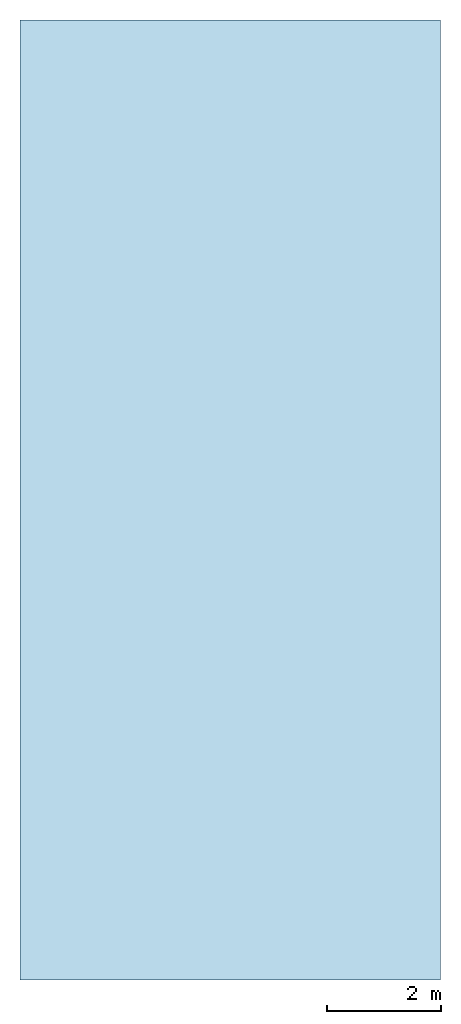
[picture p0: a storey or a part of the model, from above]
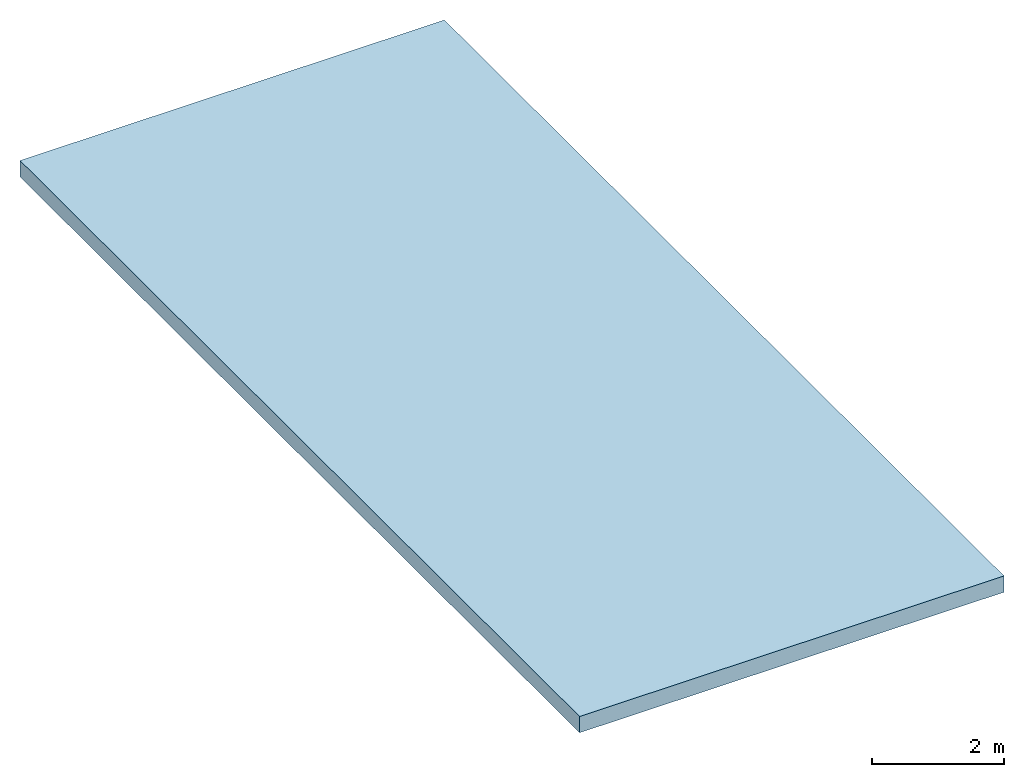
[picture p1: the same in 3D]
Properties of the parts of a building model (IFC2X3)

# File
Description: ViewDefinition [CoordinationView_V2.0]
File name: 0001
Time: 2020-11-30T17:44:46
Written by: The EXPRESS Data Manager Version 5.02.0100.07 : 28 Aug 2013
Made in: 21.0.0.383 - Exporter 21.0.0.383 - IU alternativa 21.0.0.383
Comment: STEP Physical File produced by: The EXPRESS Data Manager Version 5.02.0100.07 : 28 Aug 2013 * Module: EDMstepFileFactory/EDMstandAlone * Creation date: Mon Nov 30 17:44:46 2020 * Host: DESKTOP-IT14RNR * Database: C:\Users\CYPE\AppData\Local\Temp\9540b35c-920c-4d57-9700-88821f75c136\3319a0d3-95b9-443c-a24a-ebdda90667f6\ifc * Database version: 5507 * Database creation date: Mon Nov 30 17:44:29 2020 * Schema: IFC2X3 * Model: DataRepository.ifc * Model creation date: Mon Nov 30 17:44:29 2020 * Header model: DataRepository.ifc_HeaderModel * Header model creation date: Mon Nov 30 17:44:29 2020 * EDMuser: sdai-user * EDMgroup: sdai-group * License ID and type: 5605 : Permanent license. Expiry date: * EDMstepFileFactory options: 020000

# IfcProject, 0001
LongName: Nombre de proyecto; Phase: Estado de proyecto

# IfcSite, Default
RefLatitude: 40, 25, 13, 9643; RefLongitude: -3, -42, -20, -772056; RefElevation: 0 m

# IfcBuilding
Pset_BuildingCommon - NumberOfStoreys: 2

# IfcBuildingStorey: Nivel:Nivel 1 (2)
Name | LongName | Elevation (m)
Nivel 1 | Nivel 1 | 0
Nivel 2 | Nivel 2 | 3

# IfcCurtainWall: Muro cortina:Muro cortina - 300 x 200 cm, Muro cortina:Muro cortina - 300 x 200 cm:166910
In: Nivel 1
Type - Pset_CurtainWallCommon - IsExternal: no; Reference: Muro cortina - 300 x 200 cm
Type - Pset_QuantityTakeOff - Reference: Muro cortina - 300 x 200 cm
Pset_CurtainWallCommon - IsExternal: yes

# IfcDoor: Puerta de 1 hoja:80 x 210 cm, Puerta de 1 hoja:80 x 210 cm:166070
In: Nivel 1
Type - ParameterTakesPrecedence: no; Sizeable: no; Material: <Unnamed> (3), Madera - Castaño
Type - Pset_DoorCommon - IsExternal: no; Reference: 80 x 210 cm; ThermalTransmittance: 3.7021 kg/K/s3
Type - Pset_QuantityTakeOff - Reference: 80 x 210 cm
OverallHeight: 2.1 m; OverallWidth: 0.8 m; Material: Madera - Castaño

# IfcFurnishingElement: M_Chair-Breuer:M_Chair-Breuer (28)
In: Nivel 1
Type - Material: Steel, Chrome Plated, Textile - Bamboo Weave
Type - Pset_QuantityTakeOff - Reference: M_Chair-Breuer
Material: Textile - Bamboo Weave, Steel, Chrome Plated
Name (M_Chair-Breuer:M_Chair-Breuer:...)
165478
165479
165480
165481
165593
165594
165595
165596
165632
165633
165634
165635
165734
165735
165736
165737
165777
165778
165779
165780
165822
165823
165824
165825
165863
165864
165865
165866

# IfcFurnishingElement: M_Table-Dining Round w Chairs:0915mm Diameter (7)
In: Nivel 1
Type - Material: Laminate, Linen, Matte, Pine
Type - Pset_QuantityTakeOff - Reference: 0915mm Diameter
Material: Pine, Laminate, Linen, Matte
Name (M_Table-Dining Round w Chairs:0915mm Diameter:...)
165477
165592
165631
165733
165776
165821
165862

# IfcMember: Montante rectangular:Montante rectangular - 5 x 10 cm (31)
In: Nivel 1
Type - PredefinedType: MULLION; Material: <Unnamed>
Type - Pset_MemberCommon - IsExternal: no; Reference: Montante rectangular - 5 x 10 cm
Type - Pset_QuantityTakeOff - Reference: Montante rectangular - 5 x 10 cm
Pset_MemberCommon - IsExternal: yes
Name (Montante rectangular:Montante rectangular - 5 x 10 cm:...) | Span (m)
166943 | 0.958333
166944 | 0.958333
166955 | 0.958333
166956 | 0.958333
166957 | 0.958333
167001 | 0.983333
167002 | 0.958333
167003 | 0.958333
167004 | 0.983333
167005 | 0.983333
167006 | 0.958333
167007 | 0.983333
167008 | 0.958333
167009 | 0.983333
167010 | 0.958333
167011 | 1.7125
167012 | 1.7625
167013 | 1.7625
167014 | 1.7125
167015 | 1.7125
167016 | 1.7625
167017 | 1.7625
167018 | 1.7125
167101 | 1.7875
167102 | 1.7875
167103 | 1.8125
167104 | 1.8125
167105 | 1.7875
167106 | 1.8125
167107 | 1.8125
167108 | 1.7875

# IfcPlate: Panel de sistema:Acristalado (12)
In: Nivel 1
Type - PredefinedType: CURTAIN_PANEL; Material: Cristal
Type - Pset_PlateCommon - IsExternal: no; Reference: Acristalado; ThermalTransmittance: 6.7069 kg/K/s3
Type - Pset_QuantityTakeOff - Reference: Acristalado
Pset_PlateCommon - IsExternal: yes
Name (Panel de sistema:Acristalado:...)
166941
166946
166948
166950
166984
166985
166986
166987
166989
166990
166991
166992

# IfcSlab: Suelo:Por defecto - 30 cm (2)
Type - PredefinedType: FLOOR; Material: Suelos por defecto 0.3 m
Type - Pset_QuantityTakeOff - Reference: Por defecto - 30 cm
Type - Pset_ReinforcementBarPitchOfSlab - Reference: Por defecto - 30 cm
Type - Pset_SlabCommon - IsExternal: no; Reference: Por defecto - 30 cm
Pset_QuantityTakeOff - sets with these values: 2
Pset_SlabCommon - LoadBearing: no; PitchAngle: 0 deg
Name (Suelo:Por defecto - 30 cm:...) | In
166729 | Nivel 1
166811 | Nivel 2

# IfcWallStandardCase: Muro básico:Partición con capa de yeso (3)
In: Nivel 1
Type - PredefinedType: STANDARD; Material: Enlucido - Blanco 0.015 m, Ladrillo de cerámica hueco doble 0.07 m, Enlucido - Blanco 0.015 m
Type - Pset_QuantityTakeOff - Reference: Partición con capa de yeso
Type - Pset_ReinforcementBarPitchOfWall - Reference: Partición con capa de yeso
Type - Pset_WallCommon - Reference: Partición con capa de yeso; IsExternal: no
Pset_QuantityTakeOff - sets with these values: 2
Pset_WallCommon - ExtendToStructure: no; LoadBearing: no
Name (Muro básico:Partición con capa de yeso:...)
163541
163542
163543

# IfcWindow: Ventana simple:100 x 100 cm (9)
In: Nivel 1
Type - ParameterTakesPrecedence: no; Sizeable: no; Material: Madera - Castaño, Vidrio, Piedra - Gris
Type - Pset_QuantityTakeOff - Reference: 100 x 100 cm
Type - Pset_WindowCommon - IsExternal: no; Reference: 100 x 100 cm; ThermalTransmittance: 6.7069 kg/K/s3
OverallHeight: 2.3 m; OverallWidth: 1 m; Material: Vidrio, Madera - Castaño, Piedra - Gris
Name (Ventana simple:100 x 100 cm:...)
164008
164121
164156
164180
164181
164192
164193
164194
164195
